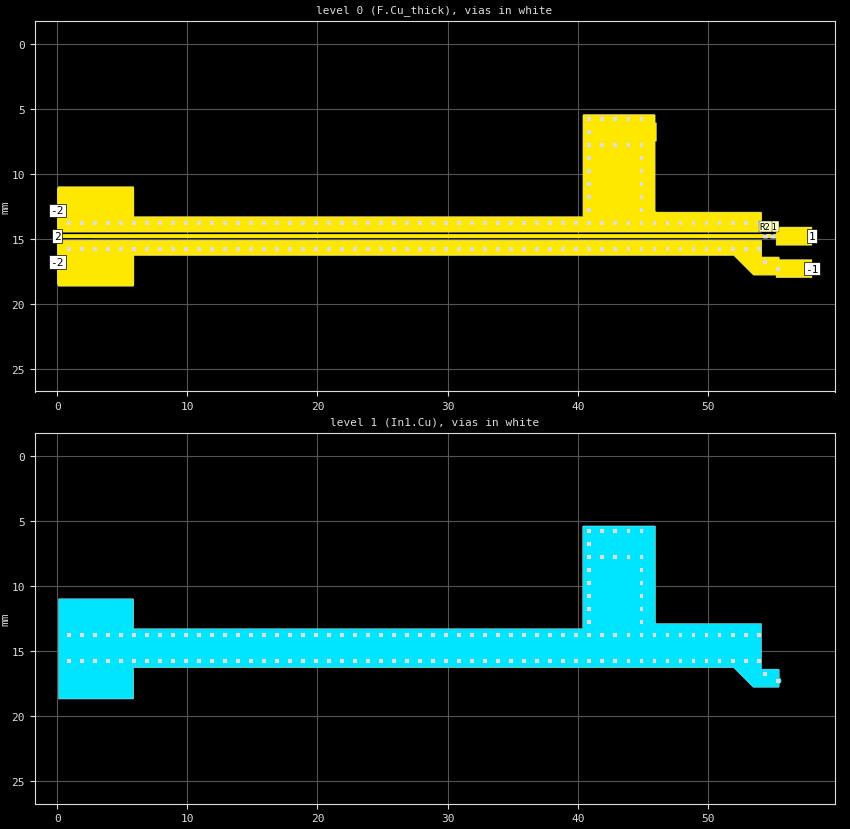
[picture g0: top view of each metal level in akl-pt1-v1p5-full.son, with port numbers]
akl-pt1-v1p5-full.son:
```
FTYP SONPROJ 19 ! Sonnet Project File
VER 18.54
HEADER
LIC antikernel2.1.51813
DAT 08/11/2022 23:21:57
BUILT_BY_CREATED dxf 18.54 08/11/2022 23:14:47
BUILT_BY_SAVED sonnet 18.54
MDATE 08/11/2022 23:21:57
HDATE 08/11/2022 23:21:57
ANN Created by dxfgeo, Sonnet Software Inc.
END HEADER
DIM
ANG DEG
CAP PF
CON /OH
FREQ GHZ
IND NH
LNG MM
RES OH
END DIM
CONTROL
VARSWP
OPTIONS  -dj
SPEED 1
CACHE_ABS 2
Q_ACC N
END CONTROL
GEO
TMET "Free Space" 0 FREESPACE 376.7303136 0 0 0
BMET "Free Space" 0 FREESPACE 376.7303136 0 0 0
MET "Copper_1oz+plated_thick_up" 1 TMM 58000000 0.5 0.0432 2
MET "Copper_1oz+plated_thin" 4 NOR 58000000 0.5 0.0432 
MET "Copper_0.5oz_thin" 2 NOR 58000000 0.5 0.0175 
MET "Copper_1oz+plated_thick_down" 3 TMM 58000000 0.5 0.0432 2 CDVY TDWN
BOX 4 58 25 2320 1000 20 0
      10 1 1 0 0 0 0 "Air"
      0.2021 3.61 1 0.0092 0 0 0 "Isola_FR408HR"
      1.1938 3.61 1 0.0092 0 0 0 "Isola_FR408HR"
      0.2021 3.61 1 0.0092 0 0 0 "Isola_FR408HR"
      10 1 1 0 0 0 0 "Air"
TECHLAY METAL F.Cu_thick <UNSPECIFIED> -1 0 CAD F.Cu drawing 
0 0 0 N 150 1 1 100 100 0 0 0 Y
END
END
TECHLAY VIA Via1 <UNSPECIFIED> -7 0 CAD Via1 drawing 
VIA POLYGON
0 0 -1 N 321 1 1 100 100 0 0 0 Y
TOLEVEL 3 RING NOCOVERS
END
END
TECHLAY METAL F.Cu_thin <UNSPECIFIED> -2 0 CAD F.Cu_thin drawing 
0 0 1 N 154 1 1 100 100 0 0 0 Y
END
END
TECHLAY METAL In1.Cu <UNSPECIFIED> -3 0 CAD In1.Cu drawing 
1 0 2 N 157 1 1 100 100 0 0 0 Y
END
END
TECHLAY METAL In2.Cu <UNSPECIFIED> -4 0 CAD In2.Cu drawing 
2 0 2 N 160 1 1 100 100 0 0 0 Y
END
END
TECHLAY METAL B.Cu_thin <UNSPECIFIED> -6 0 CAD B.Cu_thin drawing 
3 0 1 N 163 1 1 100 100 0 0 0 Y
END
END
TECHLAY METAL B.Cu_thick <UNSPECIFIED> -5 0 CAD B.Cu drawing 
3 0 3 N 165 1 1 100 100 0 0 0 Y
END
END
LORGN 0 25 U 
POR1 BOX
POLY 224 1
41
-2 50 0 0 0 0 12.82 
POR1 BOX
POLY 225 1
10
2 50 0 0 0 0 14.8 
POR1 BOX
POLY 228 1
9
-1 50 0 0 0 58 17.3 
POR1 BOX
POLY 228 1
23
-2 50 0 0 0 0 16.78 
POR1 BOX
POLY 229 1
15
1 50 0 0 0 58 14.8 
SMD 0 "R1"
ID 240
GNDREF FLOAT
SBOX 54.89875 54.99625 14.75125 14.84875
PBSHW N
LPOS 54.9475 14.75125
TYPE SPARAM 1
SMDP 0 55.045 14.8 R 3 1 
EXSMDP
GNDREF FLOAT
TERMW FEED
END EXSMDP
SMDP 0 54.85 14.8 L 4 2 
EXSMDP
GNDREF FLOAT
TERMW FEED
END EXSMDP
END
SMD 0 "R2"
ID 269
GNDREF FLOAT
SBOX 54.35 54.45 14.75 14.85
PBSHW N
LPOS 54.4 14.75
TYPE SPARAM 2
SMDP 0 54.5 14.8 R 5 1 
EXSMDP
GNDREF FLOAT
TERMW FEED
END EXSMDP
SMDP 0 54.3 14.8 L 6 2 
EXSMDP
GNDREF FLOAT
TERMW FEED
END EXSMDP
END
NUM 137
0 13 0 N 3 1 1 100 100 0 0 0 Y
TLAYNAM F.Cu_thick INH
USER_DAT FromImport
54.5 14.955
54.5 14.645
54.65 14.645
54.65 14.65
54.7 14.65
54.7 14.645
54.85 14.645
54.85 14.955
54.7 14.955
54.7 14.95
54.65 14.95
54.65 14.955
54.5 14.955
END
0 45 0 N 224 1 1 100 100 0 0 0 Y
TLAYNAM F.Cu_thick INH
USER_DAT FromImport
54.089 14.493
54.133 14.468
54.15 14.421
54.15 13.024
54.149 13.011
54.124 12.967
54.076 12.95
46.129 12.95
46.11 12.953
46.1 12.955
46.091 12.953
46.061 12.945
46.022 12.934
45.966 12.878
45.95 12.82
45.945 12.8
45.947 12.79
45.95 12.771
45.95 7.5
46.05 7.5
46.05 6.1
45.95 6.1
45.95 5.524
45.949 5.511
45.924 5.467
45.876 5.45
40.474 5.45
40.461 5.451
40.417 5.476
40.4 5.524
40.4 13.3
5.9 13.3
5.9 11.074
5.899 11.061
5.874 11.017
5.826 11
0.124 11
0.111 11.001
0.067 11.026
0.05 11.074
0.05 11.145
0 11.145
0 14.495
54.076 14.495
54.089 14.493
END
0 23 0 N 225 1 1 100 100 0 0 0 Y
TLAYNAM F.Cu_thick INH
USER_DAT FromImport
54.3 14.645
54.15 14.645
54.15 14.653
54.138 14.649
54.123 14.646
54.108 14.645
2.692 14.645
2.677 14.646
2.662 14.649
2.659 14.65
0 14.65
0 14.95
2.659 14.95
2.662 14.951
2.677 14.954
2.692 14.955
54.108 14.955
54.123 14.954
54.138 14.951
54.15 14.947
54.15 14.955
54.3 14.955
54.3 14.645
END
0 32 0 N 228 1 1 100 100 0 0 0 Y
TLAYNAM F.Cu_thick INH
USER_DAT FromImport
5.839 18.649
5.883 18.624
5.9 18.576
5.9 16.3
52 16.3
53.483 17.783
53.531 17.8
55.245 17.8
55.245 18
58 18
58 16.6
55.5 16.6
55.5 16.474
55.499 16.461
55.474 16.417
55.426 16.4
54.15 16.4
54.15 15.18
54.149 15.167
54.124 15.123
54.076 15.106
5.5 15.106
5.5 15.105
0 15.105
0 18.455
0.05 18.455
0.05 18.576
0.051 18.589
0.076 18.633
0.124 18.65
5.826 18.65
5.839 18.649
END
0 17 0 N 229 1 1 100 100 0 0 0 Y
TLAYNAM F.Cu_thick INH
USER_DAT FromImport
58 14.1
55.245 14.1
55.245 14.645
55.05 14.645
55.05 14.759
55.049 14.762
55.046 14.777
55.045 14.792
55.045 14.808
55.046 14.823
55.049 14.838
55.05 14.841
55.05 14.955
55.245 14.955
55.245 15.5
58 15.5
58 14.1
END
VIA POLYGON
0 5 -1 N 7 1 1 100 100 0 0 0 Y
TOLEVEL 3 RING NOCOVERS
TLAYNAM Via1 INH
USER_DAT FromImport
55.25 17.45
55.25 17.15
55.55 17.15
55.55 17.45
55.25 17.45
END
VIA POLYGON
0 5 -1 N 8 1 1 100 100 0 0 0 Y
TOLEVEL 3 RING NOCOVERS
TLAYNAM Via1 INH
USER_DAT FromImport
54.25 16.95
54.25 16.65
54.55 16.65
54.55 16.95
54.25 16.95
END
VIA POLYGON
0 5 -1 N 9 1 1 100 100 0 0 0 Y
TOLEVEL 3 RING NOCOVERS
TLAYNAM Via1 INH
USER_DAT FromImport
28.75 15.95
28.75 15.65
29.05 15.65
29.05 15.95
28.75 15.95
END
VIA POLYGON
0 5 -1 N 10 1 1 100 100 0 0 0 Y
TOLEVEL 3 RING NOCOVERS
TLAYNAM Via1 INH
USER_DAT FromImport
29.75 15.95
29.75 15.65
30.05 15.65
30.05 15.95
29.75 15.95
END
VIA POLYGON
0 5 -1 N 11 1 1 100 100 0 0 0 Y
TOLEVEL 3 RING NOCOVERS
TLAYNAM Via1 INH
USER_DAT FromImport
30.75 15.95
30.75 15.65
31.05 15.65
31.05 15.95
30.75 15.95
END
VIA POLYGON
0 5 -1 N 12 1 1 100 100 0 0 0 Y
TOLEVEL 3 RING NOCOVERS
TLAYNAM Via1 INH
USER_DAT FromImport
31.75 15.95
31.75 15.65
32.05 15.65
32.05 15.95
31.75 15.95
END
VIA POLYGON
0 5 -1 N 13 1 1 100 100 0 0 0 Y
TOLEVEL 3 RING NOCOVERS
TLAYNAM Via1 INH
USER_DAT FromImport
32.75 15.95
32.75 15.65
33.05 15.65
33.05 15.95
32.75 15.95
END
VIA POLYGON
0 5 -1 N 14 1 1 100 100 0 0 0 Y
TOLEVEL 3 RING NOCOVERS
TLAYNAM Via1 INH
USER_DAT FromImport
33.75 15.95
33.75 15.65
34.05 15.65
34.05 15.95
33.75 15.95
END
VIA POLYGON
0 5 -1 N 15 1 1 100 100 0 0 0 Y
TOLEVEL 3 RING NOCOVERS
TLAYNAM Via1 INH
USER_DAT FromImport
34.75 15.95
34.75 15.65
35.05 15.65
35.05 15.95
34.75 15.95
END
VIA POLYGON
0 5 -1 N 16 1 1 100 100 0 0 0 Y
TOLEVEL 3 RING NOCOVERS
TLAYNAM Via1 INH
USER_DAT FromImport
35.75 15.95
35.75 15.65
36.05 15.65
36.05 15.95
35.75 15.95
END
VIA POLYGON
0 5 -1 N 17 1 1 100 100 0 0 0 Y
TOLEVEL 3 RING NOCOVERS
TLAYNAM Via1 INH
USER_DAT FromImport
36.75 15.95
36.75 15.65
37.05 15.65
37.05 15.95
36.75 15.95
END
VIA POLYGON
0 5 -1 N 18 1 1 100 100 0 0 0 Y
TOLEVEL 3 RING NOCOVERS
TLAYNAM Via1 INH
USER_DAT FromImport
37.75 15.95
37.75 15.65
38.05 15.65
38.05 15.95
37.75 15.95
END
VIA POLYGON
0 5 -1 N 19 1 1 100 100 0 0 0 Y
TOLEVEL 3 RING NOCOVERS
TLAYNAM Via1 INH
USER_DAT FromImport
38.75 15.95
38.75 15.65
39.05 15.65
39.05 15.95
38.75 15.95
END
VIA POLYGON
0 5 -1 N 20 1 1 100 100 0 0 0 Y
TOLEVEL 3 RING NOCOVERS
TLAYNAM Via1 INH
USER_DAT FromImport
39.75 15.95
39.75 15.65
40.05 15.65
40.05 15.95
39.75 15.95
END
VIA POLYGON
0 5 -1 N 21 1 1 100 100 0 0 0 Y
TOLEVEL 3 RING NOCOVERS
TLAYNAM Via1 INH
USER_DAT FromImport
40.75 15.95
40.75 15.65
41.05 15.65
41.05 15.95
40.75 15.95
END
VIA POLYGON
0 5 -1 N 22 1 1 100 100 0 0 0 Y
TOLEVEL 3 RING NOCOVERS
TLAYNAM Via1 INH
USER_DAT FromImport
41.75 15.95
41.75 15.65
42.05 15.65
42.05 15.95
41.75 15.95
END
VIA POLYGON
0 5 -1 N 23 1 1 100 100 0 0 0 Y
TOLEVEL 3 RING NOCOVERS
TLAYNAM Via1 INH
USER_DAT FromImport
42.75 15.95
42.75 15.65
43.05 15.65
43.05 15.95
42.75 15.95
END
VIA POLYGON
0 5 -1 N 24 1 1 100 100 0 0 0 Y
TOLEVEL 3 RING NOCOVERS
TLAYNAM Via1 INH
USER_DAT FromImport
43.75 15.95
43.75 15.65
44.05 15.65
44.05 15.95
43.75 15.95
END
VIA POLYGON
0 5 -1 N 25 1 1 100 100 0 0 0 Y
TOLEVEL 3 RING NOCOVERS
TLAYNAM Via1 INH
USER_DAT FromImport
44.75 15.95
44.75 15.65
45.05 15.65
45.05 15.95
44.75 15.95
END
VIA POLYGON
0 5 -1 N 26 1 1 100 100 0 0 0 Y
TOLEVEL 3 RING NOCOVERS
TLAYNAM Via1 INH
USER_DAT FromImport
45.75 15.95
45.75 15.65
46.05 15.65
46.05 15.95
45.75 15.95
END
VIA POLYGON
0 5 -1 N 27 1 1 100 100 0 0 0 Y
TOLEVEL 3 RING NOCOVERS
TLAYNAM Via1 INH
USER_DAT FromImport
46.75 15.95
46.75 15.65
47.05 15.65
47.05 15.95
46.75 15.95
END
VIA POLYGON
0 5 -1 N 28 1 1 100 100 0 0 0 Y
TOLEVEL 3 RING NOCOVERS
TLAYNAM Via1 INH
USER_DAT FromImport
47.75 15.95
47.75 15.65
48.05 15.65
48.05 15.95
47.75 15.95
END
VIA POLYGON
0 5 -1 N 29 1 1 100 100 0 0 0 Y
TOLEVEL 3 RING NOCOVERS
TLAYNAM Via1 INH
USER_DAT FromImport
48.75 15.95
48.75 15.65
49.05 15.65
49.05 15.95
48.75 15.95
END
VIA POLYGON
0 5 -1 N 30 1 1 100 100 0 0 0 Y
TOLEVEL 3 RING NOCOVERS
TLAYNAM Via1 INH
USER_DAT FromImport
49.75 15.95
49.75 15.65
50.05 15.65
50.05 15.95
49.75 15.95
END
VIA POLYGON
0 5 -1 N 31 1 1 100 100 0 0 0 Y
TOLEVEL 3 RING NOCOVERS
TLAYNAM Via1 INH
USER_DAT FromImport
50.75 15.95
50.75 15.65
51.05 15.65
51.05 15.95
50.75 15.95
END
VIA POLYGON
0 5 -1 N 32 1 1 100 100 0 0 0 Y
TOLEVEL 3 RING NOCOVERS
TLAYNAM Via1 INH
USER_DAT FromImport
51.75 15.95
51.75 15.65
52.05 15.65
52.05 15.95
51.75 15.95
END
VIA POLYGON
0 5 -1 N 33 1 1 100 100 0 0 0 Y
TOLEVEL 3 RING NOCOVERS
TLAYNAM Via1 INH
USER_DAT FromImport
52.75 15.95
52.75 15.65
53.05 15.65
53.05 15.95
52.75 15.95
END
VIA POLYGON
0 5 -1 N 34 1 1 100 100 0 0 0 Y
TOLEVEL 3 RING NOCOVERS
TLAYNAM Via1 INH
USER_DAT FromImport
53.75 15.95
53.75 15.65
54.05 15.65
54.05 15.95
53.75 15.95
END
VIA POLYGON
0 5 -1 N 35 1 1 100 100 0 0 0 Y
TOLEVEL 3 RING NOCOVERS
TLAYNAM Via1 INH
USER_DAT FromImport
28.75 13.95
28.75 13.65
29.05 13.65
29.05 13.95
28.75 13.95
END
VIA POLYGON
0 5 -1 N 36 1 1 100 100 0 0 0 Y
TOLEVEL 3 RING NOCOVERS
TLAYNAM Via1 INH
USER_DAT FromImport
29.75 13.95
29.75 13.65
30.05 13.65
30.05 13.95
29.75 13.95
END
VIA POLYGON
0 5 -1 N 37 1 1 100 100 0 0 0 Y
TOLEVEL 3 RING NOCOVERS
TLAYNAM Via1 INH
USER_DAT FromImport
30.75 13.95
30.75 13.65
31.05 13.65
31.05 13.95
30.75 13.95
END
VIA POLYGON
0 5 -1 N 38 1 1 100 100 0 0 0 Y
TOLEVEL 3 RING NOCOVERS
TLAYNAM Via1 INH
USER_DAT FromImport
31.75 13.95
31.75 13.65
32.05 13.65
32.05 13.95
31.75 13.95
END
VIA POLYGON
0 5 -1 N 39 1 1 100 100 0 0 0 Y
TOLEVEL 3 RING NOCOVERS
TLAYNAM Via1 INH
USER_DAT FromImport
32.75 13.95
32.75 13.65
33.05 13.65
33.05 13.95
32.75 13.95
END
VIA POLYGON
0 5 -1 N 40 1 1 100 100 0 0 0 Y
TOLEVEL 3 RING NOCOVERS
TLAYNAM Via1 INH
USER_DAT FromImport
33.75 13.95
33.75 13.65
34.05 13.65
34.05 13.95
33.75 13.95
END
VIA POLYGON
0 5 -1 N 41 1 1 100 100 0 0 0 Y
TOLEVEL 3 RING NOCOVERS
TLAYNAM Via1 INH
USER_DAT FromImport
34.75 13.95
34.75 13.65
35.05 13.65
35.05 13.95
34.75 13.95
END
VIA POLYGON
0 5 -1 N 42 1 1 100 100 0 0 0 Y
TOLEVEL 3 RING NOCOVERS
TLAYNAM Via1 INH
USER_DAT FromImport
35.75 13.95
35.75 13.65
36.05 13.65
36.05 13.95
35.75 13.95
END
VIA POLYGON
0 5 -1 N 43 1 1 100 100 0 0 0 Y
TOLEVEL 3 RING NOCOVERS
TLAYNAM Via1 INH
USER_DAT FromImport
36.75 13.95
36.75 13.65
37.05 13.65
37.05 13.95
36.75 13.95
END
VIA POLYGON
0 5 -1 N 44 1 1 100 100 0 0 0 Y
TOLEVEL 3 RING NOCOVERS
TLAYNAM Via1 INH
USER_DAT FromImport
37.75 13.95
37.75 13.65
38.05 13.65
38.05 13.95
37.75 13.95
END
VIA POLYGON
0 5 -1 N 45 1 1 100 100 0 0 0 Y
TOLEVEL 3 RING NOCOVERS
TLAYNAM Via1 INH
USER_DAT FromImport
38.75 13.95
38.75 13.65
39.05 13.65
39.05 13.95
38.75 13.95
END
VIA POLYGON
0 5 -1 N 46 1 1 100 100 0 0 0 Y
TOLEVEL 3 RING NOCOVERS
TLAYNAM Via1 INH
USER_DAT FromImport
39.75 13.95
39.75 13.65
40.05 13.65
40.05 13.95
39.75 13.95
END
VIA POLYGON
0 5 -1 N 47 1 1 100 100 0 0 0 Y
TOLEVEL 3 RING NOCOVERS
TLAYNAM Via1 INH
USER_DAT FromImport
40.75 13.95
40.75 13.65
41.05 13.65
41.05 13.95
40.75 13.95
END
VIA POLYGON
0 5 -1 N 48 1 1 100 100 0 0 0 Y
TOLEVEL 3 RING NOCOVERS
TLAYNAM Via1 INH
USER_DAT FromImport
41.75 13.95
41.75 13.65
42.05 13.65
42.05 13.95
41.75 13.95
END
VIA POLYGON
0 5 -1 N 49 1 1 100 100 0 0 0 Y
TOLEVEL 3 RING NOCOVERS
TLAYNAM Via1 INH
USER_DAT FromImport
42.75 13.95
42.75 13.65
43.05 13.65
43.05 13.95
42.75 13.95
END
VIA POLYGON
0 5 -1 N 50 1 1 100 100 0 0 0 Y
TOLEVEL 3 RING NOCOVERS
TLAYNAM Via1 INH
USER_DAT FromImport
43.75 13.95
43.75 13.65
44.05 13.65
44.05 13.95
43.75 13.95
END
VIA POLYGON
0 5 -1 N 51 1 1 100 100 0 0 0 Y
TOLEVEL 3 RING NOCOVERS
TLAYNAM Via1 INH
USER_DAT FromImport
44.75 13.95
44.75 13.65
45.05 13.65
45.05 13.95
44.75 13.95
END
VIA POLYGON
0 5 -1 N 52 1 1 100 100 0 0 0 Y
TOLEVEL 3 RING NOCOVERS
TLAYNAM Via1 INH
USER_DAT FromImport
45.75 13.95
45.75 13.65
46.05 13.65
46.05 13.95
45.75 13.95
END
VIA POLYGON
0 5 -1 N 53 1 1 100 100 0 0 0 Y
TOLEVEL 3 RING NOCOVERS
TLAYNAM Via1 INH
USER_DAT FromImport
46.75 13.95
46.75 13.65
47.05 13.65
47.05 13.95
46.75 13.95
END
VIA POLYGON
0 5 -1 N 54 1 1 100 100 0 0 0 Y
TOLEVEL 3 RING NOCOVERS
TLAYNAM Via1 INH
USER_DAT FromImport
47.75 13.95
47.75 13.65
48.05 13.65
48.05 13.95
47.75 13.95
END
VIA POLYGON
0 5 -1 N 55 1 1 100 100 0 0 0 Y
TOLEVEL 3 RING NOCOVERS
TLAYNAM Via1 INH
USER_DAT FromImport
48.75 13.95
48.75 13.65
49.05 13.65
49.05 13.95
48.75 13.95
END
VIA POLYGON
0 5 -1 N 56 1 1 100 100 0 0 0 Y
TOLEVEL 3 RING NOCOVERS
TLAYNAM Via1 INH
USER_DAT FromImport
49.75 13.95
49.75 13.65
50.05 13.65
50.05 13.95
49.75 13.95
END
VIA POLYGON
0 5 -1 N 57 1 1 100 100 0 0 0 Y
TOLEVEL 3 RING NOCOVERS
TLAYNAM Via1 INH
USER_DAT FromImport
50.75 13.95
50.75 13.65
51.05 13.65
51.05 13.95
50.75 13.95
END
VIA POLYGON
0 5 -1 N 58 1 1 100 100 0 0 0 Y
TOLEVEL 3 RING NOCOVERS
TLAYNAM Via1 INH
USER_DAT FromImport
51.75 13.95
51.75 13.65
52.05 13.65
52.05 13.95
51.75 13.95
END
VIA POLYGON
0 5 -1 N 59 1 1 100 100 0 0 0 Y
TOLEVEL 3 RING NOCOVERS
TLAYNAM Via1 INH
USER_DAT FromImport
52.75 13.95
52.75 13.65
53.05 13.65
53.05 13.95
52.75 13.95
END
VIA POLYGON
0 5 -1 N 60 1 1 100 100 0 0 0 Y
TOLEVEL 3 RING NOCOVERS
TLAYNAM Via1 INH
USER_DAT FromImport
53.75 13.95
53.75 13.65
54.05 13.65
54.05 13.95
53.75 13.95
END
VIA POLYGON
0 5 -1 N 61 1 1 100 100 0 0 0 Y
TOLEVEL 3 RING NOCOVERS
TLAYNAM Via1 INH
USER_DAT FromImport
40.75 12.95
40.75 12.65
41.05 12.65
41.05 12.95
40.75 12.95
END
VIA POLYGON
0 5 -1 N 62 1 1 100 100 0 0 0 Y
TOLEVEL 3 RING NOCOVERS
TLAYNAM Via1 INH
USER_DAT FromImport
44.75 12.95
44.75 12.65
45.05 12.65
45.05 12.95
44.75 12.95
END
VIA POLYGON
0 5 -1 N 63 1 1 100 100 0 0 0 Y
TOLEVEL 3 RING NOCOVERS
TLAYNAM Via1 INH
USER_DAT FromImport
40.75 11.95
40.75 11.65
41.05 11.65
41.05 11.95
40.75 11.95
END
VIA POLYGON
0 5 -1 N 64 1 1 100 100 0 0 0 Y
TOLEVEL 3 RING NOCOVERS
TLAYNAM Via1 INH
USER_DAT FromImport
44.75 11.95
44.75 11.65
45.05 11.65
45.05 11.95
44.75 11.95
END
VIA POLYGON
0 5 -1 N 65 1 1 100 100 0 0 0 Y
TOLEVEL 3 RING NOCOVERS
TLAYNAM Via1 INH
USER_DAT FromImport
40.75 10.95
40.75 10.65
41.05 10.65
41.05 10.95
40.75 10.95
END
VIA POLYGON
0 5 -1 N 66 1 1 100 100 0 0 0 Y
TOLEVEL 3 RING NOCOVERS
TLAYNAM Via1 INH
USER_DAT FromImport
44.75 10.95
44.75 10.65
45.05 10.65
45.05 10.95
44.75 10.95
END
VIA POLYGON
0 5 -1 N 67 1 1 100 100 0 0 0 Y
TOLEVEL 3 RING NOCOVERS
TLAYNAM Via1 INH
USER_DAT FromImport
40.75 9.95
40.75 9.65
41.05 9.65
41.05 9.95
40.75 9.95
END
VIA POLYGON
0 5 -1 N 68 1 1 100 100 0 0 0 Y
TOLEVEL 3 RING NOCOVERS
TLAYNAM Via1 INH
USER_DAT FromImport
44.75 9.95
44.75 9.65
45.05 9.65
45.05 9.95
44.75 9.95
END
VIA POLYGON
0 5 -1 N 69 1 1 100 100 0 0 0 Y
TOLEVEL 3 RING NOCOVERS
TLAYNAM Via1 INH
USER_DAT FromImport
40.75 8.95
40.75 8.65
41.05 8.65
41.05 8.95
40.75 8.95
END
VIA POLYGON
0 5 -1 N 70 1 1 100 100 0 0 0 Y
TOLEVEL 3 RING NOCOVERS
TLAYNAM Via1 INH
USER_DAT FromImport
44.75 8.95
44.75 8.65
45.05 8.65
45.05 8.95
44.75 8.95
END
VIA POLYGON
0 5 -1 N 71 1 1 100 100 0 0 0 Y
TOLEVEL 3 RING NOCOVERS
TLAYNAM Via1 INH
USER_DAT FromImport
40.75 7.95
40.75 7.65
41.05 7.65
41.05 7.95
40.75 7.95
END
VIA POLYGON
0 5 -1 N 72 1 1 100 100 0 0 0 Y
TOLEVEL 3 RING NOCOVERS
TLAYNAM Via1 INH
USER_DAT FromImport
41.75 7.95
41.75 7.65
42.05 7.65
42.05 7.95
41.75 7.95
END
VIA POLYGON
0 5 -1 N 73 1 1 100 100 0 0 0 Y
TOLEVEL 3 RING NOCOVERS
TLAYNAM Via1 INH
USER_DAT FromImport
42.75 7.95
42.75 7.65
43.05 7.65
43.05 7.95
42.75 7.95
END
VIA POLYGON
0 5 -1 N 74 1 1 100 100 0 0 0 Y
TOLEVEL 3 RING NOCOVERS
TLAYNAM Via1 INH
USER_DAT FromImport
43.75 7.95
43.75 7.65
44.05 7.65
44.05 7.95
43.75 7.95
END
VIA POLYGON
0 5 -1 N 75 1 1 100 100 0 0 0 Y
TOLEVEL 3 RING NOCOVERS
TLAYNAM Via1 INH
USER_DAT FromImport
44.75 7.95
44.75 7.65
45.05 7.65
45.05 7.95
44.75 7.95
END
VIA POLYGON
0 5 -1 N 76 1 1 100 100 0 0 0 Y
TOLEVEL 3 RING NOCOVERS
TLAYNAM Via1 INH
USER_DAT FromImport
40.75 6.95
40.75 6.65
41.05 6.65
41.05 6.95
40.75 6.95
END
VIA POLYGON
0 5 -1 N 77 1 1 100 100 0 0 0 Y
TOLEVEL 3 RING NOCOVERS
TLAYNAM Via1 INH
USER_DAT FromImport
40.75 5.95
40.75 5.65
41.05 5.65
41.05 5.95
40.75 5.95
END
VIA POLYGON
0 5 -1 N 78 1 1 100 100 0 0 0 Y
TOLEVEL 3 RING NOCOVERS
TLAYNAM Via1 INH
USER_DAT FromImport
41.75 5.95
41.75 5.65
42.05 5.65
42.05 5.95
41.75 5.95
END
VIA POLYGON
0 5 -1 N 79 1 1 100 100 0 0 0 Y
TOLEVEL 3 RING NOCOVERS
TLAYNAM Via1 INH
USER_DAT FromImport
42.75 5.95
42.75 5.65
43.05 5.65
43.05 5.95
42.75 5.95
END
VIA POLYGON
0 5 -1 N 80 1 1 100 100 0 0 0 Y
TOLEVEL 3 RING NOCOVERS
TLAYNAM Via1 INH
USER_DAT FromImport
43.75 5.95
43.75 5.65
44.05 5.65
44.05 5.95
43.75 5.95
END
VIA POLYGON
0 5 -1 N 81 1 1 100 100 0 0 0 Y
TOLEVEL 3 RING NOCOVERS
TLAYNAM Via1 INH
USER_DAT FromImport
44.75 5.95
44.75 5.65
45.05 5.65
45.05 5.95
44.75 5.95
END
VIA POLYGON
0 5 -1 N 82 1 1 100 100 0 0 0 Y
TOLEVEL 3 RING NOCOVERS
TLAYNAM Via1 INH
USER_DAT FromImport
19.75 13.95
19.75 13.65
20.05 13.65
20.05 13.95
19.75 13.95
END
VIA POLYGON
0 5 -1 N 83 1 1 100 100 0 0 0 Y
TOLEVEL 3 RING NOCOVERS
TLAYNAM Via1 INH
USER_DAT FromImport
20.75 13.95
20.75 13.65
21.05 13.65
21.05 13.95
20.75 13.95
END
VIA POLYGON
0 5 -1 N 84 1 1 100 100 0 0 0 Y
TOLEVEL 3 RING NOCOVERS
TLAYNAM Via1 INH
USER_DAT FromImport
21.75 13.95
21.75 13.65
22.05 13.65
22.05 13.95
21.75 13.95
END
VIA POLYGON
0 5 -1 N 85 1 1 100 100 0 0 0 Y
TOLEVEL 3 RING NOCOVERS
TLAYNAM Via1 INH
USER_DAT FromImport
22.75 13.95
22.75 13.65
23.05 13.65
23.05 13.95
22.75 13.95
END
VIA POLYGON
0 5 -1 N 86 1 1 100 100 0 0 0 Y
TOLEVEL 3 RING NOCOVERS
TLAYNAM Via1 INH
USER_DAT FromImport
23.75 13.95
23.75 13.65
24.05 13.65
24.05 13.95
23.75 13.95
END
VIA POLYGON
0 5 -1 N 87 1 1 100 100 0 0 0 Y
TOLEVEL 3 RING NOCOVERS
TLAYNAM Via1 INH
USER_DAT FromImport
24.75 13.95
24.75 13.65
25.05 13.65
25.05 13.95
24.75 13.95
END
VIA POLYGON
0 5 -1 N 88 1 1 100 100 0 0 0 Y
TOLEVEL 3 RING NOCOVERS
TLAYNAM Via1 INH
USER_DAT FromImport
25.75 13.95
25.75 13.65
26.05 13.65
26.05 13.95
25.75 13.95
END
VIA POLYGON
0 5 -1 N 89 1 1 100 100 0 0 0 Y
TOLEVEL 3 RING NOCOVERS
TLAYNAM Via1 INH
USER_DAT FromImport
26.75 13.95
26.75 13.65
27.05 13.65
27.05 13.95
26.75 13.95
END
VIA POLYGON
0 5 -1 N 90 1 1 100 100 0 0 0 Y
TOLEVEL 3 RING NOCOVERS
TLAYNAM Via1 INH
USER_DAT FromImport
27.75 13.95
27.75 13.65
28.05 13.65
28.05 13.95
27.75 13.95
END
VIA POLYGON
0 5 -1 N 91 1 1 100 100 0 0 0 Y
TOLEVEL 3 RING NOCOVERS
TLAYNAM Via1 INH
USER_DAT FromImport
26.75 15.95
26.75 15.65
27.05 15.65
27.05 15.95
26.75 15.95
END
VIA POLYGON
0 5 -1 N 92 1 1 100 100 0 0 0 Y
TOLEVEL 3 RING NOCOVERS
TLAYNAM Via1 INH
USER_DAT FromImport
27.75 15.95
27.75 15.65
28.05 15.65
28.05 15.95
27.75 15.95
END
VIA POLYGON
0 5 -1 N 93 1 1 100 100 0 0 0 Y
TOLEVEL 3 RING NOCOVERS
TLAYNAM Via1 INH
USER_DAT FromImport
0.75 15.95
0.75 15.65
1.05 15.65
1.05 15.95
0.75 15.95
END
VIA POLYGON
0 5 -1 N 94 1 1 100 100 0 0 0 Y
TOLEVEL 3 RING NOCOVERS
TLAYNAM Via1 INH
USER_DAT FromImport
1.75 15.95
1.75 15.65
2.05 15.65
2.05 15.95
1.75 15.95
END
VIA POLYGON
0 5 -1 N 95 1 1 100 100 0 0 0 Y
TOLEVEL 3 RING NOCOVERS
TLAYNAM Via1 INH
USER_DAT FromImport
2.75 15.95
2.75 15.65
3.05 15.65
3.05 15.95
2.75 15.95
END
VIA POLYGON
0 5 -1 N 96 1 1 100 100 0 0 0 Y
TOLEVEL 3 RING NOCOVERS
TLAYNAM Via1 INH
USER_DAT FromImport
3.75 15.95
3.75 15.65
4.05 15.65
4.05 15.95
3.75 15.95
END
VIA POLYGON
0 5 -1 N 97 1 1 100 100 0 0 0 Y
TOLEVEL 3 RING NOCOVERS
TLAYNAM Via1 INH
USER_DAT FromImport
4.75 15.95
4.75 15.65
5.05 15.65
5.05 15.95
4.75 15.95
END
VIA POLYGON
0 5 -1 N 98 1 1 100 100 0 0 0 Y
TOLEVEL 3 RING NOCOVERS
TLAYNAM Via1 INH
USER_DAT FromImport
5.75 15.95
5.75 15.65
6.05 15.65
6.05 15.95
5.75 15.95
END
VIA POLYGON
0 5 -1 N 99 1 1 100 100 0 0 0 Y
TOLEVEL 3 RING NOCOVERS
TLAYNAM Via1 INH
USER_DAT FromImport
6.75 15.95
6.75 15.65
7.05 15.65
7.05 15.95
6.75 15.95
END
VIA POLYGON
0 5 -1 N 100 1 1 100 100 0 0 0 Y
TOLEVEL 3 RING NOCOVERS
TLAYNAM Via1 INH
USER_DAT FromImport
7.75 15.95
7.75 15.65
8.05 15.65
8.05 15.95
7.75 15.95
END
VIA POLYGON
0 5 -1 N 101 1 1 100 100 0 0 0 Y
TOLEVEL 3 RING NOCOVERS
TLAYNAM Via1 INH
USER_DAT FromImport
8.75 15.95
8.75 15.65
9.05 15.65
9.05 15.95
8.75 15.95
END
VIA POLYGON
0 5 -1 N 102 1 1 100 100 0 0 0 Y
TOLEVEL 3 RING NOCOVERS
TLAYNAM Via1 INH
USER_DAT FromImport
9.75 15.95
9.75 15.65
10.05 15.65
10.05 15.95
9.75 15.95
END
VIA POLYGON
0 5 -1 N 103 1 1 100 100 0 0 0 Y
TOLEVEL 3 RING NOCOVERS
TLAYNAM Via1 INH
USER_DAT FromImport
10.75 15.95
10.75 15.65
11.05 15.65
11.05 15.95
10.75 15.95
END
VIA POLYGON
0 5 -1 N 104 1 1 100 100 0 0 0 Y
TOLEVEL 3 RING NOCOVERS
TLAYNAM Via1 INH
USER_DAT FromImport
11.75 15.95
11.75 15.65
12.05 15.65
12.05 15.95
11.75 15.95
END
VIA POLYGON
0 5 -1 N 105 1 1 100 100 0 0 0 Y
TOLEVEL 3 RING NOCOVERS
TLAYNAM Via1 INH
USER_DAT FromImport
12.75 15.95
12.75 15.65
13.05 15.65
13.05 15.95
12.75 15.95
END
VIA POLYGON
0 5 -1 N 106 1 1 100 100 0 0 0 Y
TOLEVEL 3 RING NOCOVERS
TLAYNAM Via1 INH
USER_DAT FromImport
13.75 15.95
13.75 15.65
14.05 15.65
14.05 15.95
13.75 15.95
END
VIA POLYGON
0 5 -1 N 107 1 1 100 100 0 0 0 Y
TOLEVEL 3 RING NOCOVERS
TLAYNAM Via1 INH
USER_DAT FromImport
14.75 15.95
14.75 15.65
15.05 15.65
15.05 15.95
14.75 15.95
END
VIA POLYGON
0 5 -1 N 108 1 1 100 100 0 0 0 Y
TOLEVEL 3 RING NOCOVERS
TLAYNAM Via1 INH
USER_DAT FromImport
15.75 15.95
15.75 15.65
16.05 15.65
16.05 15.95
15.75 15.95
END
VIA POLYGON
0 5 -1 N 109 1 1 100 100 0 0 0 Y
TOLEVEL 3 RING NOCOVERS
TLAYNAM Via1 INH
USER_DAT FromImport
16.75 15.95
16.75 15.65
17.05 15.65
17.05 15.95
16.75 15.95
END
VIA POLYGON
0 5 -1 N 110 1 1 100 100 0 0 0 Y
TOLEVEL 3 RING NOCOVERS
TLAYNAM Via1 INH
USER_DAT FromImport
17.75 15.95
17.75 15.65
18.05 15.65
18.05 15.95
17.75 15.95
END
VIA POLYGON
0 5 -1 N 111 1 1 100 100 0 0 0 Y
TOLEVEL 3 RING NOCOVERS
TLAYNAM Via1 INH
USER_DAT FromImport
18.75 15.95
18.75 15.65
19.05 15.65
19.05 15.95
18.75 15.95
END
VIA POLYGON
0 5 -1 N 112 1 1 100 100 0 0 0 Y
TOLEVEL 3 RING NOCOVERS
TLAYNAM Via1 INH
USER_DAT FromImport
19.75 15.95
19.75 15.65
20.05 15.65
20.05 15.95
19.75 15.95
END
VIA POLYGON
0 5 -1 N 113 1 1 100 100 0 0 0 Y
TOLEVEL 3 RING NOCOVERS
TLAYNAM Via1 INH
USER_DAT FromImport
20.75 15.95
20.75 15.65
21.05 15.65
21.05 15.95
20.75 15.95
END
VIA POLYGON
0 5 -1 N 114 1 1 100 100 0 0 0 Y
TOLEVEL 3 RING NOCOVERS
TLAYNAM Via1 INH
USER_DAT FromImport
21.75 15.95
21.75 15.65
22.05 15.65
22.05 15.95
21.75 15.95
END
VIA POLYGON
0 5 -1 N 115 1 1 100 100 0 0 0 Y
TOLEVEL 3 RING NOCOVERS
TLAYNAM Via1 INH
USER_DAT FromImport
22.75 15.95
22.75 15.65
23.05 15.65
23.05 15.95
22.75 15.95
END
VIA POLYGON
0 5 -1 N 116 1 1 100 100 0 0 0 Y
TOLEVEL 3 RING NOCOVERS
TLAYNAM Via1 INH
USER_DAT FromImport
23.75 15.95
23.75 15.65
24.05 15.65
24.05 15.95
23.75 15.95
END
VIA POLYGON
0 5 -1 N 117 1 1 100 100 0 0 0 Y
TOLEVEL 3 RING NOCOVERS
TLAYNAM Via1 INH
USER_DAT FromImport
24.75 15.95
24.75 15.65
25.05 15.65
25.05 15.95
24.75 15.95
END
VIA POLYGON
0 5 -1 N 118 1 1 100 100 0 0 0 Y
TOLEVEL 3 RING NOCOVERS
TLAYNAM Via1 INH
USER_DAT FromImport
25.75 15.95
25.75 15.65
26.05 15.65
26.05 15.95
25.75 15.95
END
VIA POLYGON
0 5 -1 N 119 1 1 100 100 0 0 0 Y
TOLEVEL 3 RING NOCOVERS
TLAYNAM Via1 INH
USER_DAT FromImport
0.75 13.95
0.75 13.65
1.05 13.65
1.05 13.95
0.75 13.95
END
VIA POLYGON
0 5 -1 N 120 1 1 100 100 0 0 0 Y
TOLEVEL 3 RING NOCOVERS
TLAYNAM Via1 INH
USER_DAT FromImport
1.75 13.95
1.75 13.65
2.05 13.65
2.05 13.95
1.75 13.95
END
VIA POLYGON
0 5 -1 N 121 1 1 100 100 0 0 0 Y
TOLEVEL 3 RING NOCOVERS
TLAYNAM Via1 INH
USER_DAT FromImport
2.75 13.95
2.75 13.65
3.05 13.65
3.05 13.95
2.75 13.95
END
VIA POLYGON
0 5 -1 N 122 1 1 100 100 0 0 0 Y
TOLEVEL 3 RING NOCOVERS
TLAYNAM Via1 INH
USER_DAT FromImport
3.75 13.95
3.75 13.65
4.05 13.65
4.05 13.95
3.75 13.95
END
VIA POLYGON
0 5 -1 N 123 1 1 100 100 0 0 0 Y
TOLEVEL 3 RING NOCOVERS
TLAYNAM Via1 INH
USER_DAT FromImport
4.75 13.95
4.75 13.65
5.05 13.65
5.05 13.95
4.75 13.95
END
VIA POLYGON
0 5 -1 N 124 1 1 100 100 0 0 0 Y
TOLEVEL 3 RING NOCOVERS
TLAYNAM Via1 INH
USER_DAT FromImport
5.75 13.95
5.75 13.65
6.05 13.65
6.05 13.95
5.75 13.95
END
VIA POLYGON
0 5 -1 N 125 1 1 100 100 0 0 0 Y
TOLEVEL 3 RING NOCOVERS
TLAYNAM Via1 INH
USER_DAT FromImport
6.75 13.95
6.75 13.65
7.05 13.65
7.05 13.95
6.75 13.95
END
VIA POLYGON
0 5 -1 N 126 1 1 100 100 0 0 0 Y
TOLEVEL 3 RING NOCOVERS
TLAYNAM Via1 INH
USER_DAT FromImport
7.75 13.95
7.75 13.65
8.05 13.65
8.05 13.95
7.75 13.95
END
VIA POLYGON
0 5 -1 N 127 1 1 100 100 0 0 0 Y
TOLEVEL 3 RING NOCOVERS
TLAYNAM Via1 INH
USER_DAT FromImport
8.75 13.95
8.75 13.65
9.05 13.65
9.05 13.95
8.75 13.95
END
VIA POLYGON
0 5 -1 N 128 1 1 100 100 0 0 0 Y
TOLEVEL 3 RING NOCOVERS
TLAYNAM Via1 INH
USER_DAT FromImport
9.75 13.95
9.75 13.65
10.05 13.65
10.05 13.95
9.75 13.95
END
VIA POLYGON
0 5 -1 N 129 1 1 100 100 0 0 0 Y
TOLEVEL 3 RING NOCOVERS
TLAYNAM Via1 INH
USER_DAT FromImport
10.75 13.95
10.75 13.65
11.05 13.65
11.05 13.95
10.75 13.95
END
VIA POLYGON
0 5 -1 N 130 1 1 100 100 0 0 0 Y
TOLEVEL 3 RING NOCOVERS
TLAYNAM Via1 INH
USER_DAT FromImport
11.75 13.95
11.75 13.65
12.05 13.65
12.05 13.95
11.75 13.95
END
VIA POLYGON
0 5 -1 N 131 1 1 100 100 0 0 0 Y
TOLEVEL 3 RING NOCOVERS
TLAYNAM Via1 INH
USER_DAT FromImport
12.75 13.95
12.75 13.65
13.05 13.65
13.05 13.95
12.75 13.95
END
VIA POLYGON
0 5 -1 N 132 1 1 100 100 0 0 0 Y
TOLEVEL 3 RING NOCOVERS
TLAYNAM Via1 INH
USER_DAT FromImport
13.75 13.95
13.75 13.65
14.05 13.65
14.05 13.95
13.75 13.95
END
VIA POLYGON
0 5 -1 N 133 1 1 100 100 0 0 0 Y
TOLEVEL 3 RING NOCOVERS
TLAYNAM Via1 INH
USER_DAT FromImport
14.75 13.95
14.75 13.65
15.05 13.65
15.05 13.95
14.75 13.95
END
VIA POLYGON
0 5 -1 N 134 1 1 100 100 0 0 0 Y
TOLEVEL 3 RING NOCOVERS
TLAYNAM Via1 INH
USER_DAT FromImport
15.75 13.95
15.75 13.65
16.05 13.65
16.05 13.95
15.75 13.95
END
VIA POLYGON
0 5 -1 N 135 1 1 100 100 0 0 0 Y
TOLEVEL 3 RING NOCOVERS
TLAYNAM Via1 INH
USER_DAT FromImport
16.75 13.95
16.75 13.65
17.05 13.65
17.05 13.95
16.75 13.95
END
VIA POLYGON
0 5 -1 N 136 1 1 100 100 0 0 0 Y
TOLEVEL 3 RING NOCOVERS
TLAYNAM Via1 INH
USER_DAT FromImport
17.75 13.95
17.75 13.65
18.05 13.65
18.05 13.95
17.75 13.95
END
VIA POLYGON
0 5 -1 N 137 1 1 100 100 0 0 0 Y
TOLEVEL 3 RING NOCOVERS
TLAYNAM Via1 INH
USER_DAT FromImport
18.75 13.95
18.75 13.65
19.05 13.65
19.05 13.95
18.75 13.95
END
1 67 2 N 331 1 1 100 100 0 0 0 Y
TLAYNAM In1.Cu INH
USER_DAT FromImport
5.868925 18.67935
5.882925 18.64435
5.882925 16.29335
51.982925 16.29335
53.468925 17.77935
53.502925 17.79335
55.433925 17.79335
55.468925 17.77935
55.482925 17.74435
55.482925 17.52235
55.489925 17.51935
55.511925 17.50735
55.531925 17.49435
55.550925 17.47835
55.567925 17.46135
55.583925 17.44235
55.596925 17.42235
55.608925 17.40035
55.617925 17.37735
55.625925 17.35435
55.629925 17.33035
55.632925 17.30535
55.632925 17.28135
55.629925 17.25635
55.625925 17.23235
55.617925 17.20935
55.608925 17.18635
55.596925 17.16435
55.583925 17.14435
55.567925 17.12535
55.550925 17.10835
55.531925 17.09235
55.511925 17.07935
55.489925 17.06735
55.482925 17.06435
55.482925 16.44235
55.468925 16.40735
55.433925 16.39335
54.132925 16.39335
54.132925 12.94235
54.118925 12.90735
54.083925 12.89335
46.050925 12.89335
46.042925 12.88835
46.029925 12.88135
46.020925 12.87835
46.016925 12.87235
46.003925 12.85935
45.997925 12.85535
45.994925 12.84635
45.987925 12.83335
45.982925 12.82535
45.982925 5.44235
45.968925 5.40735
45.933925 5.39335
40.431925 5.39335
40.396925 5.40735
40.382925 5.44235
40.382925 13.29335
5.882925 13.29335
5.882925 11.04235
5.868925 11.00735
5.833925 10.99335
0.1 10.99335
0.1 18.69335
5.833925 18.69335
5.868925 18.67935
END
END GEO
OPT
MAX -1.866e9
END OPT
VARSWP
ENABLED Y
FREQ Y AY ABS_ENTRY 0.1 8.5 -1 300 
END
END VARSWP
SMDFILES
2 "../../../../../../ceph/bulk/datasheets/Vishay/Resistors/CH/CH02016F_P/CH02016F_P_200R.s2p"
1 "../../../../../../ceph/bulk/datasheets/Vishay/Resistors/CH/CH02016F_P/CH02016F_P_250R.s2p"
END SMDFILES
```
